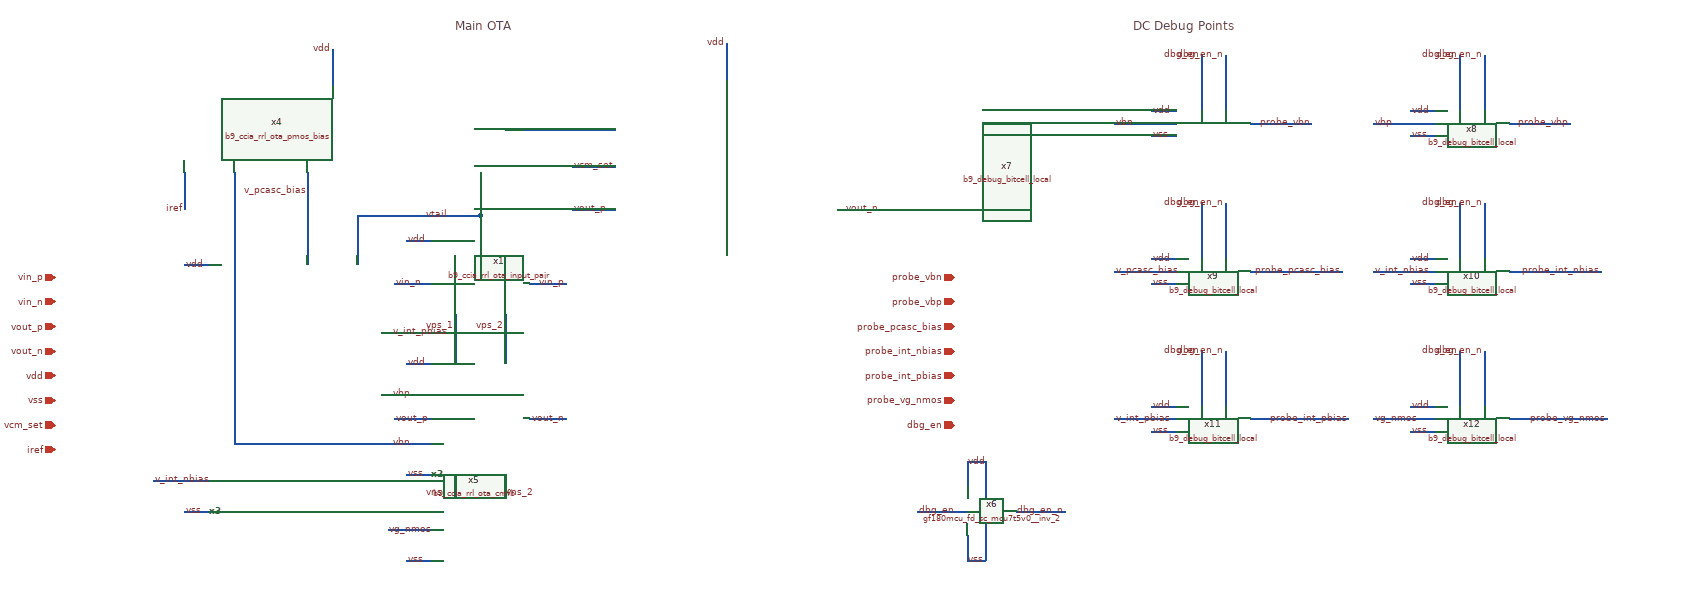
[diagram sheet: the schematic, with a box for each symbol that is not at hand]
v {xschem version=3.4.8RC file_version=1.3}
G {}
K {}
V {}
S {}
F {}
E {}
T {Main OTA} 650 -1040 0 0 0.6 0.6 {}
T {DC Debug Points} 1750 -1040 0 0 0.6 0.6 {}
N 490 -720 490 -640 {lab=vtail}
N 490 -720 690 -720 {lab=vtail}
N 690 -720 690 -680 {lab=vtail}
N 530 -430 610 -430 {lab=vbp}
N 530 -350 610 -350 {lab=vbn}
N 570 -390 610 -390 {lab=vout_p}
N 650 -560 650 -480 {lab=vps_1}
N 730 -560 730 -480 {lab=vps_2}
N 290 -350 530 -350 {lab=vbn}
N 290 -720 290 -350 {lab=vbn}
N 210 -240 250 -240 {lab=vss}
N 570 -300 610 -300 {lab=vss}
N 570 -680 610 -680 {lab=vdd}
N 210 -640 250 -640 {lab=vdd}
N 570 -480 610 -480 {lab=vdd}
N 410 -720 410 -640 {lab=v_pcasc_bias}
N 550 -390 570 -390 {lab=vout_p}
N 770 -390 810 -390 {lab=vout_n}
N 810 -390 830 -390 {lab=vout_n}
N 770 -610 810 -610 {lab=vin_p}
N 810 -610 830 -610 {lab=vin_p}
N 570 -610 610 -610 {lab=vin_n}
N 550 -610 570 -610 {lab=vin_n}
N 690 -790 690 -720 {lab=vtail}
N 290 -790 290 -720 {lab=vbn}
N 410 -790 410 -720 {lab=v_pcasc_bias}
N 210 -790 210 -730 {lab=iref}
N 450 -990 450 -930 {lab=vdd}
N 650 -300 650 -260 {lab=vns_1}
N 730 -300 730 -260 {lab=vns_2}
N 730 -860 910 -860 {lab=iref}
N 1090 -1000 1090 -940 {lab=vdd}
N 840 -800 910 -800 {lab=vcm_set}
N 840 -730 910 -730 {lab=vout_p}
N 1270 -730 1340 -730 {lab=vout_n}
N 570 -160 610 -160 {lab=vss}
N 530 -530 580 -530 {lab=v_int_pbias}
N 580 -530 640 -530 {lab=v_int_pbias}
N 160 -290 250 -290 {lab=v_int_pbias}
N 560 -210 610 -210 {lab=vg_nmos}
N 540 -210 560 -210 {lab=vg_nmos}
N 1740 -870 1820 -870 {lab=vbn}
N 1940 -870 2040 -870 {lab=probe_vbn}
N 1720 -870 1740 -870 {lab=vbn}
N 2160 -870 2240 -870 {lab=vbp}
N 2360 -870 2460 -870 {lab=probe_vbp}
N 2140 -870 2160 -870 {lab=vbp}
N 1740 -630 1820 -630 {lab=v_pcasc_bias}
N 1940 -630 2040 -630 {lab=probe_pcasc_bias}
N 1720 -630 1740 -630 {lab=v_pcasc_bias}
N 2160 -630 2240 -630 {lab=v_int_nbias}
N 2360 -630 2460 -630 {lab=probe_int_nbias}
N 2140 -630 2160 -630 {lab=v_int_nbias}
N 1740 -390 1820 -390 {lab=v_int_pbias}
N 1940 -390 2040 -390 {lab=probe_int_pbias}
N 1720 -390 1740 -390 {lab=v_int_pbias}
N 2160 -390 2240 -390 {lab=vg_nmos}
N 2360 -390 2460 -390 {lab=probe_vg_nmos}
N 2140 -390 2160 -390 {lab=vg_nmos}
N 2040 -630 2090 -630 {lab=probe_pcasc_bias}
N 2460 -630 2510 -630 {lab=probe_int_nbias}
N 2040 -390 2100 -390 {lab=probe_int_pbias}
N 2460 -390 2520 -390 {lab=probe_vg_nmos}
N 1780 -890 1820 -890 {lab=vdd}
N 1780 -850 1820 -850 {lab=vss}
N 1860 -930 1860 -890 {lab=dbg_en}
N 1860 -960 1860 -930 {lab=dbg_en}
N 1900 -960 1900 -890 {lab=dbg_en_n}
N 1860 -980 1860 -960 {lab=dbg_en}
N 1900 -980 1900 -960 {lab=dbg_en_n}
N 2200 -890 2240 -890 {lab=vdd}
N 2200 -850 2240 -850 {lab=vss}
N 2280 -930 2280 -890 {lab=dbg_en}
N 2280 -960 2280 -930 {lab=dbg_en}
N 2320 -960 2320 -890 {lab=dbg_en_n}
N 2280 -980 2280 -960 {lab=dbg_en}
N 2320 -980 2320 -960 {lab=dbg_en_n}
N 2200 -650 2240 -650 {lab=vdd}
N 2200 -610 2240 -610 {lab=vss}
N 2280 -690 2280 -650 {lab=dbg_en}
N 2280 -720 2280 -690 {lab=dbg_en}
N 2320 -720 2320 -650 {lab=dbg_en_n}
N 2280 -740 2280 -720 {lab=dbg_en}
N 2320 -740 2320 -720 {lab=dbg_en_n}
N 1780 -650 1820 -650 {lab=vdd}
N 1780 -610 1820 -610 {lab=vss}
N 1860 -690 1860 -650 {lab=dbg_en}
N 1860 -720 1860 -690 {lab=dbg_en}
N 1900 -720 1900 -650 {lab=dbg_en_n}
N 1860 -740 1860 -720 {lab=dbg_en}
N 1900 -740 1900 -720 {lab=dbg_en_n}
N 1780 -410 1820 -410 {lab=vdd}
N 1780 -370 1820 -370 {lab=vss}
N 1860 -450 1860 -410 {lab=dbg_en}
N 1860 -480 1860 -450 {lab=dbg_en}
N 1900 -480 1900 -410 {lab=dbg_en_n}
N 1860 -500 1860 -480 {lab=dbg_en}
N 1900 -500 1900 -480 {lab=dbg_en_n}
N 2200 -410 2240 -410 {lab=vdd}
N 2200 -370 2240 -370 {lab=vss}
N 2280 -450 2280 -410 {lab=dbg_en}
N 2280 -480 2280 -450 {lab=dbg_en}
N 2320 -480 2320 -410 {lab=dbg_en_n}
N 2280 -500 2280 -480 {lab=dbg_en}
N 2320 -500 2320 -480 {lab=dbg_en_n}
N 1420 -240 1480 -240 {lab=dbg_en}
N 1480 -320 1480 -280 {lab=vdd}
N 1510 -320 1510 -260 {lab=vdd}
N 1480 -320 1510 -320 {lab=vdd}
N 1480 -200 1480 -160 {lab=vss}
N 1480 -160 1510 -160 {lab=vss}
N 1510 -220 1510 -160 {lab=vss}
N 1560 -240 1640 -240 {lab=dbg_en_n}
N 1400 -240 1420 -240 {lab=dbg_en}
C {lab_wire.sym} 210 -240 0 1 {name=p1 sig_type=std_logic lab=vss}
C {lab_wire.sym} 570 -300 0 1 {name=p2 sig_type=std_logic lab=vss}
C {lab_wire.sym} 570 -680 0 1 {name=p3 sig_type=std_logic lab=vdd}
C {lab_wire.sym} 210 -640 0 1 {name=p4 sig_type=std_logic lab=vdd}
C {lab_wire.sym} 570 -480 0 1 {name=p5 sig_type=std_logic lab=vdd}
C {lab_wire.sym} 550 -390 0 1 {name=p6 sig_type=std_logic lab=vout_p}
C {lab_wire.sym} 830 -390 0 0 {name=p7 sig_type=std_logic lab=vout_n}
C {lab_wire.sym} 830 -610 0 0 {name=p8 sig_type=std_logic lab=vin_p}
C {lab_wire.sym} 550 -610 0 1 {name=p9 sig_type=std_logic lab=vin_n}
C {lab_wire.sym} 650 -540 1 1 {name=p10 sig_type=std_logic lab=vps_1}
C {lab_wire.sym} 730 -540 1 1 {name=p11 sig_type=std_logic lab=vps_2}
C {lab_wire.sym} 640 -720 0 0 {name=p12 sig_type=std_logic lab=vtail}
C {lab_wire.sym} 210 -730 1 0 {name=p13 sig_type=std_logic lab=iref}
C {lab_wire.sym} 410 -760 3 0 {name=p15 sig_type=std_logic lab=v_pcasc_bias}
C {lab_wire.sym} 450 -990 1 1 {name=p16 sig_type=std_logic lab=vdd}
C {lab_wire.sym} 1090 -1000 1 1 {name=p17 sig_type=std_logic lab=vdd}
C {lab_wire.sym} 840 -730 0 1 {name=p18 sig_type=std_logic lab=vout_p}
C {lab_wire.sym} 1340 -730 0 0 {name=p19 sig_type=std_logic lab=vout_n}
C {lab_wire.sym} 840 -800 0 1 {name=p20 sig_type=std_logic lab=vcm_set}
C {lab_wire.sym} 570 -160 0 1 {name=p21 sig_type=std_logic lab=vss}
C {iopin.sym} 0 -620 0 0 {name=p22 lab=vin_p}
C {iopin.sym} 0 -580 0 0 {name=p23 lab=vin_n}
C {iopin.sym} 0 -540 0 0 {name=p24 lab=vout_p}
C {iopin.sym} 0 -500 0 0 {name=p25 lab=vout_n}
C {iopin.sym} 0 -460 0 0 {name=p26 lab=vdd}
C {iopin.sym} 0 -420 0 0 {name=p27 lab=vss}
C {iopin.sym} 0 -380 0 0 {name=p28 lab=vcm_set}
C {iopin.sym} 0 -340 0 0 {name=p29 lab=iref}
C {lab_wire.sym} 650 -270 0 0 {name=p30 sig_type=std_logic lab=vns_1}
C {lab_wire.sym} 730 -270 0 1 {name=p31 sig_type=std_logic lab=vns_2}
C {lab_wire.sym} 580 -430 0 0 {name=p32 sig_type=std_logic lab=vbp}
C {lab_wire.sym} 580 -350 0 0 {name=p33 sig_type=std_logic lab=vbn}
C {xschem/ccia_rrl_ota/b9_ccia_rrl_ota_input_pair.sym} 610 -560 0 0 {name=x1}
C {xschem/ccia_rrl_ota/b9_ccia_rrl_ota_pmos_bias.sym} 170 -790 0 0 {name=x4}
C {xschem/ccia_rrl_ota/b9_ccia_rrl_ota_cascode.sym} 610 -300 0 0 {name=x2}
C {xschem/ccia_rrl_ota/b9_ccia_rrl_ota_cmfb.sym} 610 -160 0 0 {name=x5}
C {lab_wire.sym} 640 -530 0 0 {name=p14 sig_type=std_logic lab=v_int_pbias}
C {xschem/ccia_rrl_ota/b9_ccia_rrl_ota_cascode_bias.sym} 250 -240 0 0 {name=x3}
C {lab_wire.sym} 160 -290 0 1 {name=p34 sig_type=std_logic lab=v_int_nbias}
C {lab_wire.sym} 540 -210 0 1 {name=p35 sig_type=std_logic lab=vg_nmos}
C {xschem/debug_mux/b9_debug_bitcell_local.sym} 1820 -850 0 0 {name=x7}
C {lab_wire.sym} 1720 -870 0 1 {name=p37 sig_type=std_logic lab=vbn}
C {xschem/debug_mux/b9_debug_bitcell_local.sym} 2240 -850 0 0 {name=x8}
C {lab_wire.sym} 2140 -870 0 1 {name=p38 sig_type=std_logic lab=vbp}
C {xschem/debug_mux/b9_debug_bitcell_local.sym} 1820 -610 0 0 {name=x9}
C {lab_wire.sym} 1720 -630 0 1 {name=p39 sig_type=std_logic lab=v_pcasc_bias}
C {xschem/debug_mux/b9_debug_bitcell_local.sym} 2240 -610 0 0 {name=x10}
C {lab_wire.sym} 2140 -630 0 1 {name=p40 sig_type=std_logic lab=v_int_nbias}
C {xschem/debug_mux/b9_debug_bitcell_local.sym} 1820 -370 0 0 {name=x11}
C {lab_wire.sym} 1720 -390 0 1 {name=p41 sig_type=std_logic lab=v_int_pbias}
C {xschem/debug_mux/b9_debug_bitcell_local.sym} 2240 -370 0 0 {name=x12}
C {lab_wire.sym} 2140 -390 0 1 {name=p42 sig_type=std_logic lab=vg_nmos}
C {title.sym} 160 -40 0 0 {name=l1 author="alang"}
C {lab_wire.sym} 2040 -870 0 0 {name=p36 sig_type=std_logic lab=probe_vbn}
C {lab_wire.sym} 2460 -870 0 0 {name=p43 sig_type=std_logic lab=probe_vbp}
C {lab_wire.sym} 2090 -630 0 0 {name=p44 sig_type=std_logic lab=probe_pcasc_bias}
C {lab_wire.sym} 2510 -630 0 0 {name=p45 sig_type=std_logic lab=probe_int_nbias}
C {lab_wire.sym} 2100 -390 0 0 {name=p46 sig_type=std_logic lab=probe_int_pbias}
C {lab_wire.sym} 2520 -390 0 0 {name=p47 sig_type=std_logic lab=probe_vg_nmos}
C {iopin.sym} 1460 -620 0 0 {name=p48 lab=probe_vbn}
C {iopin.sym} 1460 -580 0 0 {name=p49 lab=probe_vbp}
C {iopin.sym} 1460 -540 0 0 {name=p50 lab=probe_pcasc_bias}
C {iopin.sym} 1460 -500 0 0 {name=p51 lab=probe_int_nbias}
C {iopin.sym} 1460 -460 0 0 {name=p52 lab=probe_int_pbias}
C {iopin.sym} 1460 -420 0 0 {name=p53 lab=probe_vg_nmos}
C {lab_wire.sym} 1780 -890 0 1 {name=p54 sig_type=std_logic lab=vdd}
C {lab_wire.sym} 1780 -850 0 1 {name=p55 sig_type=std_logic lab=vss}
C {lab_wire.sym} 1860 -980 3 0 {name=p56 sig_type=std_logic lab=dbg_en}
C {lab_wire.sym} 1900 -980 3 0 {name=p57 sig_type=std_logic lab=dbg_en_n}
C {lab_wire.sym} 2200 -890 0 1 {name=p58 sig_type=std_logic lab=vdd}
C {lab_wire.sym} 2200 -850 0 1 {name=p59 sig_type=std_logic lab=vss}
C {lab_wire.sym} 2280 -980 3 0 {name=p60 sig_type=std_logic lab=dbg_en}
C {lab_wire.sym} 2320 -980 3 0 {name=p61 sig_type=std_logic lab=dbg_en_n}
C {lab_wire.sym} 2200 -650 0 1 {name=p62 sig_type=std_logic lab=vdd}
C {lab_wire.sym} 2200 -610 0 1 {name=p63 sig_type=std_logic lab=vss}
C {lab_wire.sym} 2280 -740 3 0 {name=p64 sig_type=std_logic lab=dbg_en}
C {lab_wire.sym} 2320 -740 3 0 {name=p65 sig_type=std_logic lab=dbg_en_n}
C {lab_wire.sym} 1780 -650 0 1 {name=p66 sig_type=std_logic lab=vdd}
C {lab_wire.sym} 1780 -610 0 1 {name=p67 sig_type=std_logic lab=vss}
C {lab_wire.sym} 1860 -740 3 0 {name=p68 sig_type=std_logic lab=dbg_en}
C {lab_wire.sym} 1900 -740 3 0 {name=p69 sig_type=std_logic lab=dbg_en_n}
C {lab_wire.sym} 1780 -410 0 1 {name=p70 sig_type=std_logic lab=vdd}
C {lab_wire.sym} 1780 -370 0 1 {name=p71 sig_type=std_logic lab=vss}
C {lab_wire.sym} 1860 -500 3 0 {name=p72 sig_type=std_logic lab=dbg_en}
C {lab_wire.sym} 1900 -500 3 0 {name=p73 sig_type=std_logic lab=dbg_en_n}
C {lab_wire.sym} 2200 -410 0 1 {name=p74 sig_type=std_logic lab=vdd}
C {lab_wire.sym} 2200 -370 0 1 {name=p75 sig_type=std_logic lab=vss}
C {lab_wire.sym} 2280 -500 3 0 {name=p76 sig_type=std_logic lab=dbg_en}
C {lab_wire.sym} 2320 -500 3 0 {name=p77 sig_type=std_logic lab=dbg_en_n}
C {iopin.sym} 1460 -380 0 0 {name=p78 lab=dbg_en}
C {xschem/mcu7t5v0/gf180mcu_fd_sc_mcu7t5v0__inv_2.sym} 1480 -200 0 0 {name=x6}
C {lab_wire.sym} 1640 -240 0 0 {name=p79 sig_type=std_logic lab=dbg_en_n}
C {lab_wire.sym} 1400 -240 0 1 {name=p80 sig_type=std_logic lab=dbg_en}
C {lab_wire.sym} 1480 -320 0 1 {name=p81 sig_type=std_logic lab=vdd}
C {lab_wire.sym} 1480 -160 2 0 {name=p82 sig_type=std_logic lab=vss}
